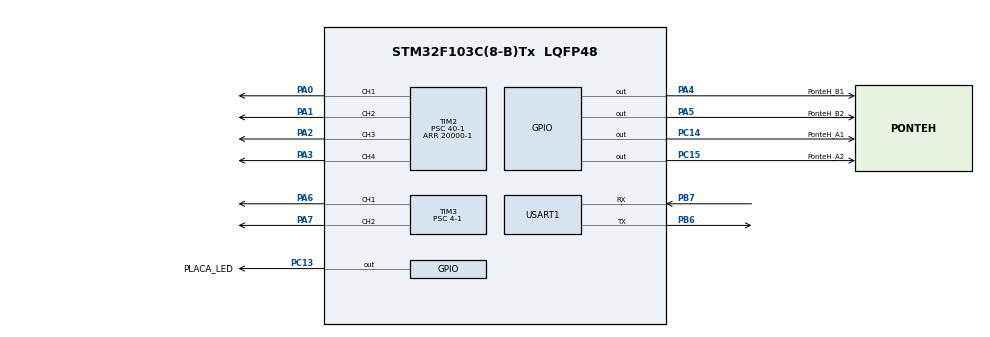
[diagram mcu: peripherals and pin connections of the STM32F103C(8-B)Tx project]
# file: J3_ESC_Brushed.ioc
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Dma.Request0=USART1_RX
Dma.USART1_RX.0.Direction=DMA_PERIPH_TO_MEMORY
Dma.USART1_RX.0.Instance=DMA1_Channel5
Dma.USART1_RX.0.MemDataAlignment=DMA_MDATAALIGN_BYTE
Dma.USART1_RX.0.MemInc=DMA_MINC_ENABLE
Dma.USART1_RX.0.Mode=DMA_NORMAL
Dma.USART1_RX.0.PeriphDataAlignment=DMA_PDATAALIGN_BYTE
Dma.USART1_RX.0.PeriphInc=DMA_PINC_DISABLE
Dma.USART1_RX.0.Priority=DMA_PRIORITY_LOW
Mcu.Family=STM32F1
Mcu.Name=STM32F103C(8-B)Tx
Mcu.Package=LQFP48
NVIC.DMA1_Channel5_IRQn=true\:0\:0\:false\:false\:true\:false\:true\:true
NVIC.PriorityGroup=NVIC_PRIORITYGROUP_4
NVIC.TIM2_IRQn=true\:0\:0\:false\:false\:true\:true\:true\:true
PA0-WKUP.Signal=S_TIM2_CH1_ETR
PA1.Signal=S_TIM2_CH2
PA13.Mode=Serial_Wire
PA13.Signal=SYS_JTMS-SWDIO
PA14.Mode=Serial_Wire
PA14.Signal=SYS_JTCK-SWCLK
PA2.Signal=S_TIM2_CH3
PA3.Signal=S_TIM2_CH4
PA4.GPIO_Label=PonteH_B1
PA4.Signal=GPIO_Output
PA5.GPIO_Label=PonteH_B2
PA5.Signal=GPIO_Output
PA6.Signal=S_TIM3_CH1
PA7.Signal=S_TIM3_CH2
PB6.Mode=Asynchronous
PB6.Signal=USART1_TX
PB7.Mode=Asynchronous
PB7.Signal=USART1_RX
PC13-TAMPER-RTC.GPIO_Label=PLACA_LED
PC13-TAMPER-RTC.Signal=GPIO_Output
PC14-OSC32_IN.GPIO_Label=PonteH_A1
PC14-OSC32_IN.Signal=GPIO_Output
PC15-OSC32_OUT.GPIO_Label=PonteH_A2
PC15-OSC32_OUT.Signal=GPIO_Output
PD0-OSC_IN.Mode=HSE-External-Oscillator
PD0-OSC_IN.Signal=RCC_OSC_IN
PD1-OSC_OUT.Mode=HSE-External-Oscillator
PD1-OSC_OUT.Signal=RCC_OSC_OUT
ProjectManager.HeapSize=0x200
ProjectManager.StackSize=0x400
ProjectManager.TargetToolchain=STM32CubeIDE
RCC.AHBFreq_Value=40000000
RCC.APB1CLKDivider=RCC_HCLK_DIV2
RCC.APB1Freq_Value=20000000
RCC.APB1TimFreq_Value=40000000
RCC.APB2Freq_Value=40000000
RCC.APB2TimFreq_Value=40000000
RCC.HCLKFreq_Value=40000000
RCC.PLLMUL=RCC_PLL_MUL5
RCC.PLLSourceVirtual=RCC_PLLSOURCE_HSE
RCC.SYSCLKFreq_VALUE=40000000
RCC.SYSCLKSource=RCC_SYSCLKSOURCE_PLLCLK
RCC.USBFreq_Value=40000000
SH.S_TIM2_CH1_ETR.0=TIM2_CH1,PWM Generation1 CH1
SH.S_TIM2_CH2.0=TIM2_CH2,PWM Generation2 CH2
SH.S_TIM2_CH3.0=TIM2_CH3,PWM Generation3 CH3
SH.S_TIM2_CH4.0=TIM2_CH4,PWM Generation4 CH4
SH.S_TIM3_CH1.0=TIM3_CH1,PWM Generation1 CH1
SH.S_TIM3_CH2.0=TIM3_CH2,PWM Generation2 CH2
TIM2.AutoReloadPreload=TIM_AUTORELOAD_PRELOAD_ENABLE
TIM2.Channel-PWM\ Generation1\ CH1=TIM_CHANNEL_1
TIM2.Channel-PWM\ Generation2\ CH2=TIM_CHANNEL_2
TIM2.Channel-PWM\ Generation3\ CH3=TIM_CHANNEL_3
TIM2.Channel-PWM\ Generation4\ CH4=TIM_CHANNEL_4
TIM2.OCFastMode_PWM-PWM\ Generation1\ CH1=TIM_OCFAST_DISABLE
TIM2.OCMode_PWM-PWM\ Generation1\ CH1=TIM_OCMODE_PWM1
TIM2.OCPolarity_1=TIM_OCPOLARITY_HIGH
TIM2.Period=20000-1
TIM2.Prescaler=40-1
TIM2.Pulse-PWM\ Generation1\ CH1=0
TIM3.AutoReloadPreload=TIM_AUTORELOAD_PRELOAD_ENABLE
TIM3.Channel-PWM\ Generation1\ CH1=TIM_CHANNEL_1
TIM3.Channel-PWM\ Generation2\ CH2=TIM_CHANNEL_2
TIM3.OCFastMode_PWM-PWM\ Generation1\ CH1=TIM_OCFAST_ENABLE
TIM3.OCFastMode_PWM-PWM\ Generation2\ CH2=TIM_OCFAST_DISABLE
TIM3.Period=1000-1
TIM3.Prescaler=4-1
USART1.VirtualMode=VM_ASYNC
VP_TIM2_VS_ClockSourceINT.Mode=Internal
VP_TIM3_VS_ClockSourceINT.Mode=Internal
board=custom

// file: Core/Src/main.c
/* USER CODE BEGIN Header */
/**
  ******************************************************************************
  * @file           : main.c
  * @brief          : Main program body
  ******************************************************************************
  * @attention
  *
  * Copyright (c) 2022 STMicroelectronics.
  * All rights reserved.
  *
  * This software is licensed under terms that can be found in the LICENSE file
  * in the root directory of this software component.
  * If no LICENSE file comes with this software, it is provided AS-IS.
  *
  ******************************************************************************
  */
/* USER CODE END Header */
#include "main.h"
#include "dma.h"
#include "tim.h"
#include "usart.h"
#include "gpio.h"

/* USER CODE BEGIN Includes */
#include "usr\main_ESC_Brushed.h"
#include "usr\J3_IBUS_FLYSKY.h"
/* USER CODE END Includes */

void SystemClock_Config(void);

int main(void)
{

  /* MCU Configuration--------------------------------------------------------*/

  /* Reset of all peripherals, Initializes the Flash interface and the Systick. */
  HAL_Init();

  /* Configure the system clock */
  SystemClock_Config();

  /* Initialize all configured peripherals */
  MX_GPIO_Init();
  MX_DMA_Init();
  MX_TIM2_Init();
  MX_TIM3_Init();
  MX_USART1_UART_Init();
  /* USER CODE BEGIN 2 */
  main_ESC_Brushed();
  /* USER CODE END 2 */

  /* Infinite loop */
  while (1)
  {

  }
}

void SystemClock_Config(void)
{
  RCC_OscInitTypeDef RCC_OscInitStruct = {0};
  RCC_ClkInitTypeDef RCC_ClkInitStruct = {0};

  /** Initializes the RCC Oscillators according to the specified parameters
  * in the RCC_OscInitTypeDef structure.
  */
  RCC_OscInitStruct.OscillatorType = RCC_OSCILLATORTYPE_HSE;
  RCC_OscInitStruct.HSEState = RCC_HSE_ON;
  RCC_OscInitStruct.HSEPredivValue = RCC_HSE_PREDIV_DIV1;
  RCC_OscInitStruct.HSIState = RCC_HSI_ON;
  RCC_OscInitStruct.PLL.PLLState = RCC_PLL_ON;
  RCC_OscInitStruct.PLL.PLLSource = RCC_PLLSOURCE_HSE;
  RCC_OscInitStruct.PLL.PLLMUL = RCC_PLL_MUL9;
  if (HAL_RCC_OscConfig(&RCC_OscInitStruct) != HAL_OK)
  {
    Error_Handler();
  }

  /** Initializes the CPU, AHB and APB buses clocks
  */
  RCC_ClkInitStruct.ClockType = RCC_CLOCKTYPE_HCLK|RCC_CLOCKTYPE_SYSCLK
                              |RCC_CLOCKTYPE_PCLK1|RCC_CLOCKTYPE_PCLK2;
  RCC_ClkInitStruct.SYSCLKSource = RCC_SYSCLKSOURCE_PLLCLK;
  RCC_ClkInitStruct.AHBCLKDivider = RCC_SYSCLK_DIV1;
  RCC_ClkInitStruct.APB1CLKDivider = RCC_HCLK_DIV2;
  RCC_ClkInitStruct.APB2CLKDivider = RCC_HCLK_DIV1;

  if (HAL_RCC_ClockConfig(&RCC_ClkInitStruct, FLASH_LATENCY_2) != HAL_OK)
  {
    Error_Handler();
  }
}

void Error_Handler(void)
{
  __disable_irq();
  while (1)
  {
  }
}
